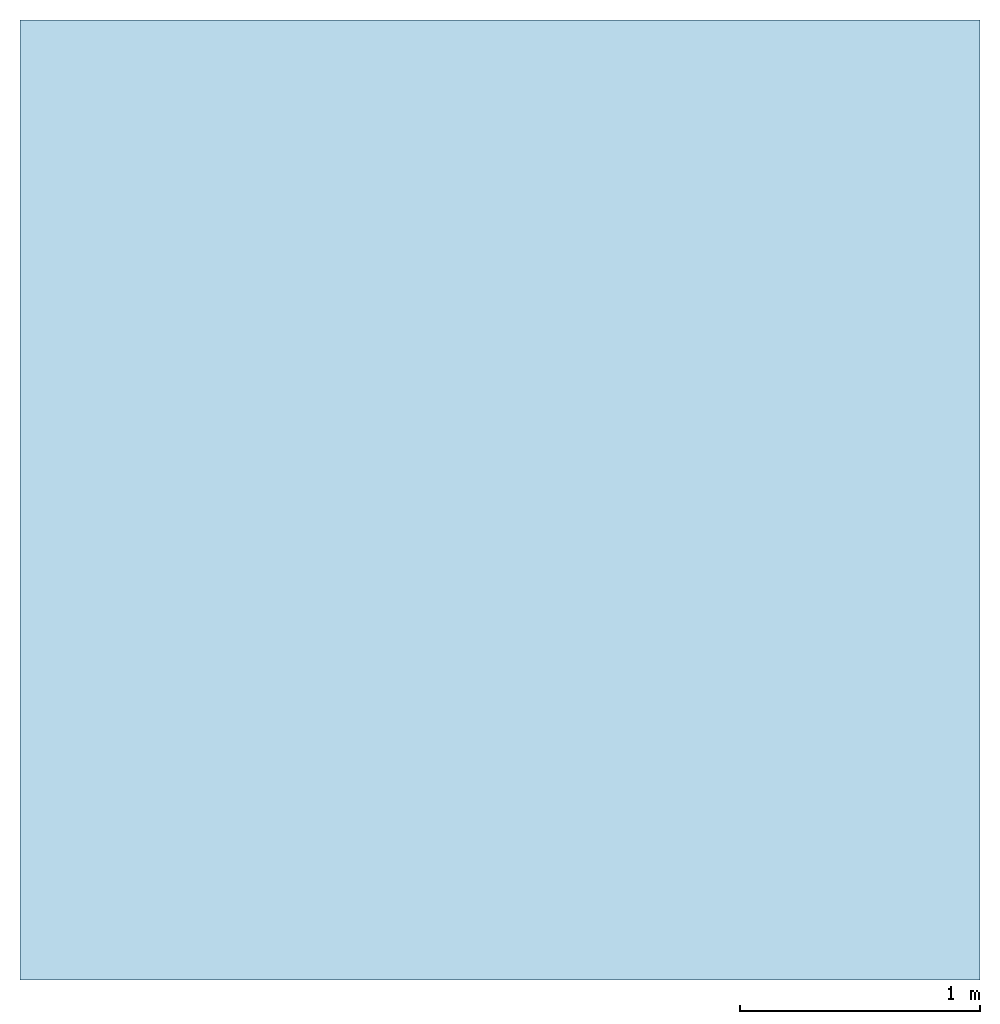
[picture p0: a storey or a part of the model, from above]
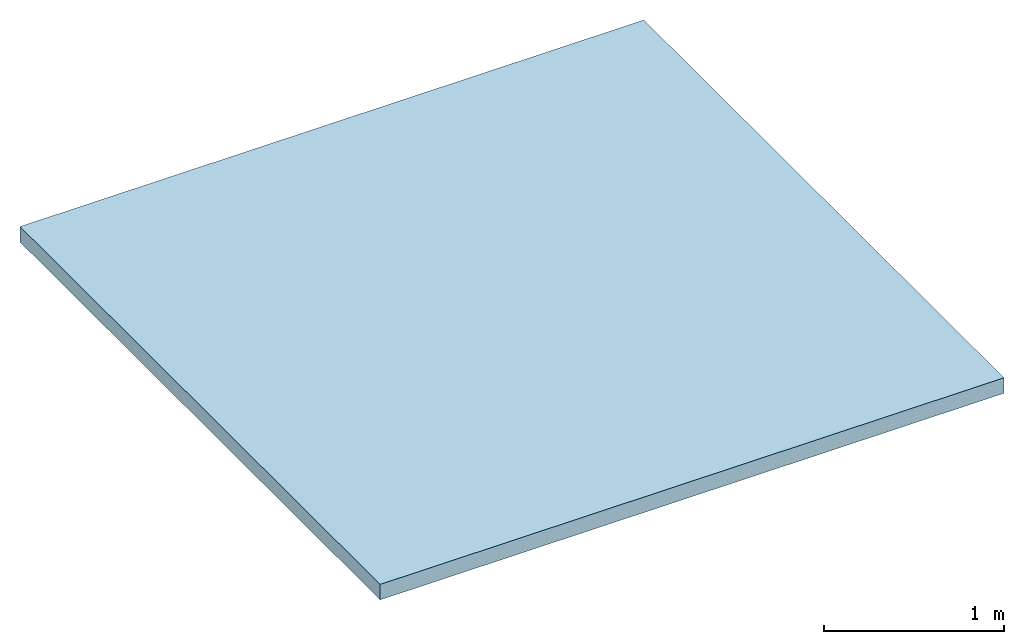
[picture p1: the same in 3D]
Properties of the parts of a building model (IFC2X3)

# File
Description: ViewDefinition [CoordinationView_V2.0]
File name: 0001
Time: 2018-05-08T14:38:18
Written by: The EXPRESS Data Manager Version 5.02.0100.07 : 28 Aug 2013
Made in: 20180328_1600(x64) - Exporter 19.0.1.1 - IU alternativa 19.0.1.1
Comment: STEP Physical File produced by: The EXPRESS Data Manager Version 5.02.0100.07 : 28 Aug 2013 * Module: EDMstepFileFactory/EDMstandAlone * Creation date: Tue May 08 14:38:18 2018 * Host: PEPEREZ * Database: C:\Users\eloy\AppData\Local\Temp\{DCF8C004-BCF9-4A5C-BDA5-3A26DA3D6A6D}\ifc * Database version: 5507 * Database creation date: Tue May 08 14:38:06 2018 * Schema: IFC2X3 * Model: DataRepository.ifc * Model creation date: Tue May 08 14:38:08 2018 * Header model: DataRepository.ifc_HeaderModel * Header model creation date: Tue May 08 14:38:08 2018 * EDMuser: sdai-user * EDMgroup: sdai-group * License ID and type: 5605 : Permanent license. Expiry date: * EDMstepFileFactory options: 020000

# IfcProject, 0001
LongName: Nombre de proyecto; Phase: Estado de proyecto

# IfcSite, Default
RefLatitude: 40, 24, 0, 5493; RefLongitude: -3, -40, -59, -880065; RefElevation: 0 mm

# IfcBuilding
Pset_BuildingCommon - NumberOfStoreys: 1

# IfcBuildingStorey, Nivel 1
LongName: Nivel 1; Elevation: 0 mm

# IfcRoof: Cubierta básica:Cubierta convencional no transitable - Protección ligera - BANTDGM7, Cubierta básica:Cubierta convencional no transitable - Protección ligera - BANTDGM7:132469
In: Nivel 1
Pset_RoofCommon - Reference: Cubierta convencional no transitable - Protección ligera - BANTDGM7; IsExternal: yes; TotalArea: 16 m2; ProjectedArea: 16 m2
Pset_ManufacturerTypeInformation - Manufacturer: Chova

# IfcSlab: Cubierta básica:Cubierta convencional no transitable - Protección ligera - BANTDGM7, Cubierta básica:Cubierta convencional no transitable - Protección ligera - BANTDGM7:132469
In: Nivel 1
PredefinedType: ROOF; Material: Laroc S 175 60 mm, Chapa grecada 45 mm
Pset_SlabCommon - Reference: Cubierta convencional no transitable - Protección ligera - BANTDGM7; IsExternal: yes; ThermalTransmittance: 1000 kg/K/s3; PitchAngle: 0 deg
Pset_ManufacturerTypeInformation - Manufacturer: Chova
